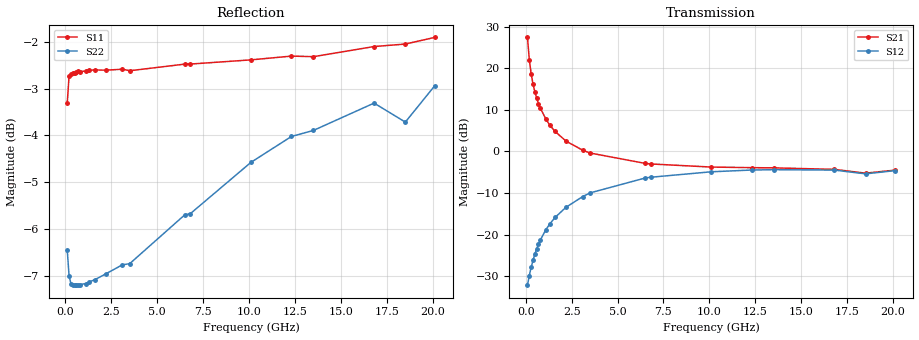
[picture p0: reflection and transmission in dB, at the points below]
!  Infineon Technologies AG
! BFR380L3 , PF131585-7, No.6, Th 09.10.01, soldered on pcb-board, measured with PP GSG850
!  Vce=0.5 V,  Ic=50.0 mA
! Common Emitter S-Parameters:  15. November 2001
#  GHz  S  MA  R  50
! f  S11  S21  S12  S22
! GHz  Mag  Ang  Mag  Ang  Mag  Ang  Mag  Ang
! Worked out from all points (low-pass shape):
!   201 points, 100 MHz to 20.1 GHz, reference 50 ohm
!   highest |S21| = 27.44 dB at 100 MHz (marker M1); lowest = -5.2 dB at 18.5 GHz (marker M2)
!   |S21| within 3 dB of the highest: start of sweep to 155.8 MHz
!   lowest |S11| = -3.3 dB at 100 MHz (marker M3), VSWR 5.31, Z = 10.2 - j14.1 ohm
!   |S11| at or under -10 dB: nowhere
!   |S22| runs from -7.2 to -2.9 dB; largest |S21 - S12| = 24
!   S11 on the Smith chart (normalised r, x): 100 MHz: 0.20, -0.28; 800 MHz: 0.15, +0.07; 3.1 GHz: 0.17, +0.40; 6.5 GHz: 0.24, +0.84; 12.3 GHz: 0.48, +1.56; 20.1 GHz: 0.97, +2.66
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0.1  0.6831 -147.3  23.54 112.0  0.02474 45.8  0.476 -123.6
0.2  0.7307 -165.0  12.68 98.6  0.03228 50.1  0.4464 -150.5
0.3  0.7333 -172.5  8.602 93.2  0.04045 55.8  0.4381 -161.4
0.4  0.7367 -177.0  6.508 89.4  0.04906 59.8  0.4367 -167.4
0.5  0.736 179.7  5.227 86.3  0.05811 62.5  0.4367 -171.4
0.6  0.7382 177.0  4.375 83.9  0.06737 64.2  0.4364 -174.4
0.7  0.7395 174.5  3.77 81.5  0.07679 65.2  0.4369 -176.7
0.8  0.7384 172.3  3.315 79.3  0.0863 65.9  0.437 -178.7
1.1  0.7397 166.5  2.453 73.4  0.1145 65.9  0.438 176.5
1.3  0.741 163.1  2.098 69.7  0.1333 65.3  0.44 173.8
1.6  0.7416 158.0  1.743 64.6  0.161 63.8  0.4423 170.3
2.2  0.7411 148.7  1.333 55.2  0.2138 59.4  0.4487 163.9
3.1  0.7429 135.9  1.037 43.1  0.2866 52.0  0.4588 155.2
3.5  0.7401 130.5  0.9589 38.4  0.3175 48.5  0.4601 151.6
6.5  0.7523 98.1  0.7198 12.4  0.4796 24.6  0.519 126.2
6.8  0.7524 95.3  0.7083 10.5  0.4901 22.2  0.5204 123.6
10.1  0.7602 72.3  0.6499 -6.8  0.57 1.5  0.5906 101.8
12.3  0.7673 61.9  0.6391 -16.4  0.5985 -10.5  0.6294 88.1
13.5  0.7662 56.9  0.6355 -21.6  0.6043 -16.6  0.6389 81.6
16.8  0.7856 45.9  0.6096 -33.1  0.5976 -30.1  0.6834 66.0
18.5  0.7904 44.1  0.5489 -40.4  0.5383 -37.7  0.6521 62.4
20.1  0.8035 37.2  0.597 -43.9  0.5889 -42.0  0.7132 53.1
